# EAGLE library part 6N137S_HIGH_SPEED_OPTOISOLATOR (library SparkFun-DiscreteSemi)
Lite-On 6N137 - High Speed Opto Isolator Opto isolator capable of data rates up to 10MBd

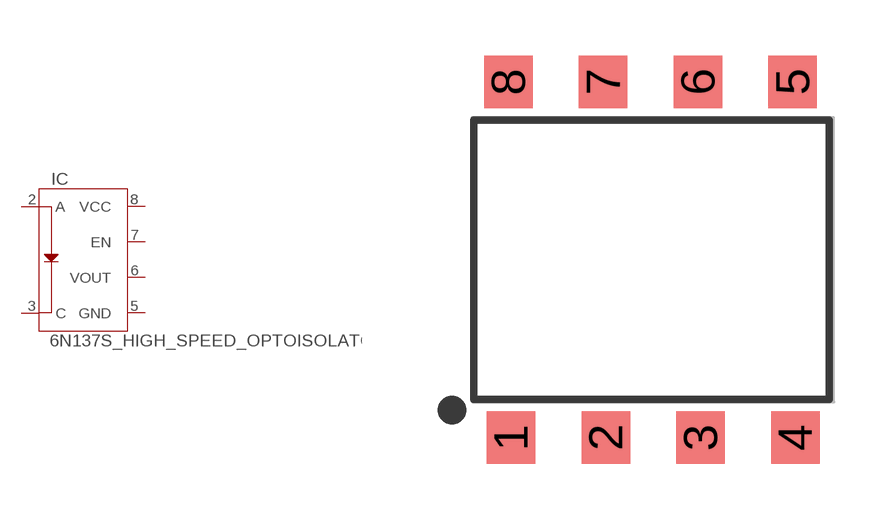
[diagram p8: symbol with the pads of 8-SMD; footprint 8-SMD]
Designator prefix IC

## 6N137S_HIGH_SPEED_OPTOISOLATOR (PROD_ID: IC-14151)  [8-SMD]
2  A
3  C
5  GND
6  VOUT
7  EN
8  VCC

## Footprint 8-SMD (pad centres in mm)
smd 1.3 x 1.4: 1 -3.96,-4.96; 2 -1.42,-4.96; 3 1.12,-4.96; 4 3.66,-4.96; 5 3.59,4.58; 6 1.05,4.58; 7 -1.49,4.58; 8 -4.03,4.58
